VERSION 5.8 ;
BUSBITCHARS "[]" ;
DIVIDERCHAR "/" ;

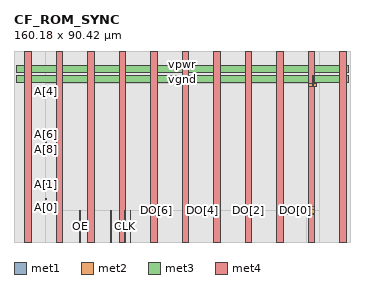
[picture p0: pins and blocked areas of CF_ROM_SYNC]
MACRO CF_ROM_SYNC
  CLASS BLOCK ;
  ORIGIN 0 0 ;
  FOREIGN CF_ROM_SYNC 0 0 ;
  SIZE 160.18 BY 90.42 ;
  PIN DO[0]
    DIRECTION OUTPUT ;
    USE SIGNAL ;
    PORT
      LAYER met1 ;
        RECT 133.68 14.95 133.875 15.38 ;
    END
  END DO[0]
  PIN DO[1]
    DIRECTION OUTPUT ;
    USE SIGNAL ;
    PORT
      LAYER met1 ;
        RECT 132.715 14.95 132.91 15.38 ;
    END
  END DO[1]
  PIN DO[2]
    DIRECTION OUTPUT ;
    USE SIGNAL ;
    PORT
      LAYER met1 ;
        RECT 111.73 14.95 111.925 15.38 ;
    END
  END DO[2]
  PIN DO[3]
    DIRECTION OUTPUT ;
    USE SIGNAL ;
    PORT
      LAYER met1 ;
        RECT 110.765 14.95 110.96 15.38 ;
    END
  END DO[3]
  PIN DO[4]
    DIRECTION OUTPUT ;
    USE SIGNAL ;
    PORT
      LAYER met1 ;
        RECT 89.78 14.95 89.975 15.38 ;
    END
  END DO[4]
  PIN DO[6]
    DIRECTION OUTPUT ;
    USE SIGNAL ;
    PORT
      LAYER met1 ;
        RECT 67.83 14.95 68.025 15.38 ;
    END
  END DO[6]
  PIN A[2]
    DIRECTION INPUT ;
    USE SIGNAL ;
    PORT
      LAYER met2 ;
        RECT 15.01 25.73 15.4 26.215 ;
    END
  END A[2]
  PIN A[1]
    DIRECTION INPUT ;
    USE SIGNAL ;
    PORT
      LAYER met2 ;
        RECT 15.01 27.13 15.4 27.615 ;
    END
  END A[1]
  PIN A[0]
    DIRECTION INPUT ;
    USE SIGNAL ;
    PORT
      LAYER met2 ;
        RECT 15.015 16.285 15.405 16.77 ;
    END
  END A[0]
  PIN A[3]
    DIRECTION INPUT ;
    USE SIGNAL ;
    PORT
      LAYER met2 ;
        RECT 15.02 20.125 15.41 20.61 ;
    END
  END A[3]
  PIN A[9]
    DIRECTION INPUT ;
    USE SIGNAL ;
    PORT
      LAYER met2 ;
        RECT 15.01 48.79 15.4 49.275 ;
    END
  END A[9]
  PIN A[8]
    DIRECTION INPUT ;
    USE SIGNAL ;
    PORT
      LAYER met2 ;
        RECT 15.01 47.39 15.4 47.875 ;
    END
  END A[8]
  PIN DO[5]
    DIRECTION OUTPUT ;
    USE SIGNAL ;
    PORT
      LAYER met1 ;
        RECT 88.815 14.95 89.01 15.38 ;
    END
  END DO[5]
  PIN vpwr
    DIRECTION INPUT ;
    USE POWER ;
    PORT
      LAYER met2 ;
        RECT 139.185 15.41 143.01 16.725 ;
        RECT 139.185 13.24 143.01 16.725 ;
      LAYER met3 ;
        RECT 126.31 13.24 143.01 13.72 ;
        RECT 1.23 80.72 158.95 83.82 ;
      LAYER met4 ;
        RECT 5 0 8.1 90.42 ;
        RECT 35 0 38.1 90.42 ;
        RECT 65 0 68.1 90.42 ;
        RECT 95 0 98.1 90.42 ;
        RECT 125 0 128.1 90.42 ;
        RECT 155 0 158.1 90.42 ;
    END
  END vpwr
  PIN vgnd
    DIRECTION INPUT ;
    USE GROUND ;
    PORT
      LAYER met2 ;
        RECT 140.215 73.965 144.04 75.28 ;
        RECT 141.89 73.965 142.37 79.02 ;
      LAYER met3 ;
        RECT 1.23 75.92 158.95 79.02 ;
      LAYER met4 ;
        RECT 20 0 23.1 90.42 ;
        RECT 50 0 53.1 90.42 ;
        RECT 80 0 83.1 90.42 ;
        RECT 110 0 113.1 90.42 ;
        RECT 140 0 143.1 90.42 ;
    END
  END vgnd
  PIN OE
    DIRECTION INPUT ;
    USE SIGNAL ;
    PORT
      LAYER met1 ;
        RECT 31.4 0 31.595 15.225 ;
    END
  END OE
  PIN EN
    DIRECTION INPUT ;
    USE SIGNAL ;
    PORT
      LAYER met1 ;
        RECT 55.23 0 55.425 15.225 ;
    END
  END EN
  PIN CLK
    DIRECTION INPUT ;
    USE SIGNAL ;
    PORT
      LAYER met1 ;
        RECT 52.535 0 52.73 15.225 ;
    END
  END CLK
  PIN RST
    DIRECTION INPUT ;
    USE SIGNAL ;
    PORT
      LAYER met1 ;
        RECT 46.085 0 46.28 15.225 ;
    END
  END RST
  PIN DO[7]
    DIRECTION OUTPUT ;
    USE SIGNAL ;
    PORT
      LAYER met1 ;
        RECT 66.865 14.95 67.06 15.38 ;
    END
  END DO[7]
  PIN A[5]
    DIRECTION INPUT ;
    USE SIGNAL ;
    PORT
      LAYER met2 ;
        RECT 15.01 72.7 15.4 73.185 ;
    END
  END A[5]
  PIN A[4]
    DIRECTION INPUT ;
    USE SIGNAL ;
    PORT
      LAYER met2 ;
        RECT 15.01 71.31 15.4 71.795 ;
    END
  END A[4]
  PIN A[6]
    DIRECTION INPUT ;
    USE SIGNAL ;
    PORT
      LAYER met2 ;
        RECT 15.01 51.03 15.4 51.515 ;
    END
  END A[6]
  PIN A[7]
    DIRECTION INPUT ;
    USE SIGNAL ;
    PORT
      LAYER met2 ;
        RECT 15.01 49.63 15.4 50.115 ;
    END
  END A[7]
  OBS
    LAYER li1 ;
      RECT 0 0 160.18 90.42 ;
    LAYER met1 ;
      RECT 0 0 15 90.42 ;
      RECT 145.18 0 160.18 90.42 ;
      RECT 15 0 31.4 15 ;
      RECT 31.595 0 46.085 15 ;
      RECT 46.28 0 52.535 15 ;
      RECT 52.73 0 55.23 15 ;
      RECT 55.425 0 66.865 15 ;
      RECT 66.865 0 67.06 14.95 ;
      RECT 67.06 0 67.83 15 ;
      RECT 67.83 0 68.025 14.95 ;
      RECT 68.025 0 88.815 15 ;
      RECT 88.815 0 89.01 14.95 ;
      RECT 89.01 0 89.78 15 ;
      RECT 89.78 0 89.975 14.95 ;
      RECT 89.975 0 110.765 15 ;
      RECT 110.765 0 110.96 14.95 ;
      RECT 110.96 0 111.73 15 ;
      RECT 111.73 0 111.925 14.95 ;
      RECT 111.925 0 132.715 15 ;
      RECT 132.715 0 132.91 14.95 ;
      RECT 132.91 0 133.68 15 ;
      RECT 133.68 0 133.875 14.95 ;
      RECT 133.875 0 145.18 15 ;
      RECT 15 75.42 145.18 90.42 ;
    LAYER met2 ;
      RECT 0 0 15 90.42 ;
      RECT 145.18 0 160.18 90.42 ;
      RECT 15 0 139.185 15 ;
      RECT 139.185 0 143.01 13.24 ;
      RECT 143.01 0 145.18 15 ;
      RECT 15 75.42 141.89 90.42 ;
      RECT 141.89 79.02 142.37 90.42 ;
      RECT 142.37 75.42 145.18 90.42 ;
  END
END CF_ROM_SYNC

END LIBRARY
